VERSION 5.7 ;
  NAMESCASESENSITIVE ON ;
  NOWIREEXTENSIONATPIN ON ;
  DIVIDERCHAR "/" ;
  BUSBITCHARS "[]" ;
UNITS
  DATABASE MICRONS 200 ;
END UNITS

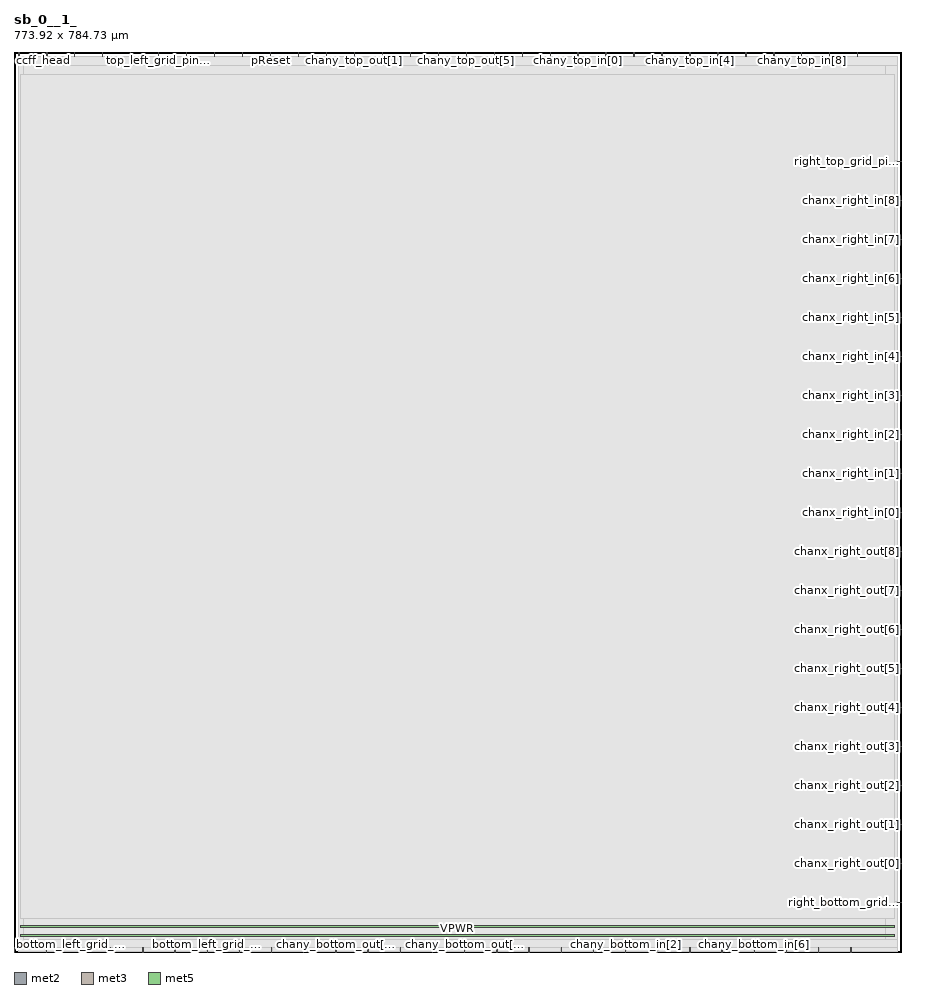
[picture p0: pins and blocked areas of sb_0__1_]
MACRO sb_0__1_
  CLASS BLOCK ;
  FOREIGN sb_0__1_ ;
  ORIGIN 0.000 0.000 ;
  SIZE 773.920 BY 784.730 ;
  PIN ccff_head
    DIRECTION INPUT ;
    PORT
      LAYER met2 ;
        RECT 4.140 780.730 4.420 784.730 ;
    END
  END ccff_head
  PIN top_left_grid_pin_1_
    DIRECTION INPUT ;
    PORT
      LAYER met2 ;
        RECT 28.520 780.730 28.800 784.730 ;
    END
  END top_left_grid_pin_1_
  PIN top_left_grid_pin_3_
    DIRECTION INPUT ;
    PORT
      LAYER met2 ;
        RECT 52.900 780.730 53.180 784.730 ;
    END
  END top_left_grid_pin_3_
  PIN top_left_grid_pin_5_
    DIRECTION INPUT ;
    PORT
      LAYER met2 ;
        RECT 77.280 780.730 77.560 784.730 ;
    END
  END top_left_grid_pin_5_
  PIN top_left_grid_pin_7_
    DIRECTION INPUT ;
    PORT
      LAYER met2 ;
        RECT 101.660 780.730 101.940 784.730 ;
    END
  END top_left_grid_pin_7_
  PIN top_left_grid_pin_9_
    DIRECTION INPUT ;
    PORT
      LAYER met2 ;
        RECT 126.040 780.730 126.320 784.730 ;
    END
  END top_left_grid_pin_9_
  PIN top_left_grid_pin_11_
    DIRECTION INPUT ;
    PORT
      LAYER met2 ;
        RECT 150.420 780.730 150.700 784.730 ;
    END
  END top_left_grid_pin_11_
  PIN top_left_grid_pin_13_
    DIRECTION INPUT ;
    PORT
      LAYER met2 ;
        RECT 174.800 780.730 175.080 784.730 ;
    END
  END top_left_grid_pin_13_
  PIN top_left_grid_pin_15_
    DIRECTION OUTPUT TRISTATE ;
    PORT
      LAYER met2 ;
        RECT 199.180 780.730 199.460 784.730 ;
    END
  END top_left_grid_pin_15_
  PIN pReset
    DIRECTION INPUT ;
    PORT
      LAYER met2 ;
        RECT 223.560 780.730 223.840 784.730 ;
    END
  END pReset
  PIN prog_clk
    DIRECTION INPUT ;
    PORT
      LAYER met2 ;
        RECT 247.940 780.730 248.220 784.730 ;
    END
  END prog_clk
  PIN chany_top_out[0]
    DIRECTION OUTPUT TRISTATE ;
    PORT
      LAYER met2 ;
        RECT 272.320 780.730 272.600 784.730 ;
    END
  END chany_top_out[0]
  PIN chany_top_out[1]
    DIRECTION OUTPUT TRISTATE ;
    PORT
      LAYER met2 ;
        RECT 296.700 780.730 296.980 784.730 ;
    END
  END chany_top_out[1]
  PIN chany_top_out[2]
    DIRECTION OUTPUT TRISTATE ;
    PORT
      LAYER met2 ;
        RECT 321.080 780.730 321.360 784.730 ;
    END
  END chany_top_out[2]
  PIN chany_top_out[3]
    DIRECTION OUTPUT TRISTATE ;
    PORT
      LAYER met2 ;
        RECT 345.460 780.730 345.740 784.730 ;
    END
  END chany_top_out[3]
  PIN chany_top_out[4]
    DIRECTION OUTPUT TRISTATE ;
    PORT
      LAYER met2 ;
        RECT 369.840 780.730 370.120 784.730 ;
    END
  END chany_top_out[4]
  PIN chany_top_out[5]
    DIRECTION OUTPUT TRISTATE ;
    PORT
      LAYER met2 ;
        RECT 394.220 780.730 394.500 784.730 ;
    END
  END chany_top_out[5]
  PIN chany_top_out[6]
    DIRECTION OUTPUT TRISTATE ;
    PORT
      LAYER met2 ;
        RECT 418.600 780.730 418.880 784.730 ;
    END
  END chany_top_out[6]
  PIN chany_top_out[7]
    DIRECTION OUTPUT TRISTATE ;
    PORT
      LAYER met2 ;
        RECT 442.980 780.730 443.260 784.730 ;
    END
  END chany_top_out[7]
  PIN chany_top_out[8]
    DIRECTION OUTPUT TRISTATE ;
    PORT
      LAYER met2 ;
        RECT 467.360 780.730 467.640 784.730 ;
    END
  END chany_top_out[8]
  PIN chany_top_in[0]
    DIRECTION INPUT ;
    PORT
      LAYER met2 ;
        RECT 491.740 780.730 492.020 784.730 ;
    END
  END chany_top_in[0]
  PIN chany_top_in[1]
    DIRECTION INPUT ;
    PORT
      LAYER met2 ;
        RECT 516.120 780.730 516.400 784.730 ;
    END
  END chany_top_in[1]
  PIN chany_top_in[2]
    DIRECTION INPUT ;
    PORT
      LAYER met2 ;
        RECT 540.500 780.730 540.780 784.730 ;
    END
  END chany_top_in[2]
  PIN chany_top_in[3]
    DIRECTION INPUT ;
    PORT
      LAYER met2 ;
        RECT 564.880 780.730 565.160 784.730 ;
    END
  END chany_top_in[3]
  PIN chany_top_in[4]
    DIRECTION INPUT ;
    PORT
      LAYER met2 ;
        RECT 589.260 780.730 589.540 784.730 ;
    END
  END chany_top_in[4]
  PIN chany_top_in[5]
    DIRECTION INPUT ;
    PORT
      LAYER met2 ;
        RECT 613.640 780.730 613.920 784.730 ;
    END
  END chany_top_in[5]
  PIN chany_top_in[6]
    DIRECTION INPUT ;
    PORT
      LAYER met2 ;
        RECT 638.020 780.730 638.300 784.730 ;
    END
  END chany_top_in[6]
  PIN chany_top_in[7]
    DIRECTION INPUT ;
    PORT
      LAYER met2 ;
        RECT 662.400 780.730 662.680 784.730 ;
    END
  END chany_top_in[7]
  PIN chany_top_in[8]
    DIRECTION INPUT ;
    PORT
      LAYER met2 ;
        RECT 686.780 780.730 687.060 784.730 ;
    END
  END chany_top_in[8]
  PIN ccff_tail
    DIRECTION OUTPUT TRISTATE ;
    PORT
      LAYER met2 ;
        RECT 711.160 780.730 711.440 784.730 ;
    END
  END ccff_tail
  PIN top_right_grid_pin_11_
    DIRECTION INPUT ;
    PORT
      LAYER met2 ;
        RECT 735.540 780.730 735.820 784.730 ;
    END
  END top_right_grid_pin_11_
  PIN right_bottom_grid_pin_12_
    DIRECTION INPUT ;
    PORT
      LAYER met3 ;
        RECT 769.920 42.880 773.920 43.480 ;
    END
  END right_bottom_grid_pin_12_
  PIN chanx_right_out[0]
    DIRECTION OUTPUT TRISTATE ;
    PORT
      LAYER met3 ;
        RECT 769.920 76.880 773.920 77.480 ;
    END
  END chanx_right_out[0]
  PIN chanx_right_out[1]
    DIRECTION OUTPUT TRISTATE ;
    PORT
      LAYER met3 ;
        RECT 769.920 110.880 773.920 111.480 ;
    END
  END chanx_right_out[1]
  PIN chanx_right_out[2]
    DIRECTION OUTPUT TRISTATE ;
    PORT
      LAYER met3 ;
        RECT 769.920 144.880 773.920 145.480 ;
    END
  END chanx_right_out[2]
  PIN chanx_right_out[3]
    DIRECTION OUTPUT TRISTATE ;
    PORT
      LAYER met3 ;
        RECT 769.920 178.880 773.920 179.480 ;
    END
  END chanx_right_out[3]
  PIN chanx_right_out[4]
    DIRECTION OUTPUT TRISTATE ;
    PORT
      LAYER met3 ;
        RECT 769.920 212.880 773.920 213.480 ;
    END
  END chanx_right_out[4]
  PIN chanx_right_out[5]
    DIRECTION OUTPUT TRISTATE ;
    PORT
      LAYER met3 ;
        RECT 769.920 246.880 773.920 247.480 ;
    END
  END chanx_right_out[5]
  PIN chanx_right_out[6]
    DIRECTION OUTPUT TRISTATE ;
    PORT
      LAYER met3 ;
        RECT 769.920 280.880 773.920 281.480 ;
    END
  END chanx_right_out[6]
  PIN chanx_right_out[7]
    DIRECTION OUTPUT TRISTATE ;
    PORT
      LAYER met3 ;
        RECT 769.920 314.880 773.920 315.480 ;
    END
  END chanx_right_out[7]
  PIN chanx_right_out[8]
    DIRECTION OUTPUT TRISTATE ;
    PORT
      LAYER met3 ;
        RECT 769.920 348.880 773.920 349.480 ;
    END
  END chanx_right_out[8]
  PIN chanx_right_in[0]
    DIRECTION INPUT ;
    PORT
      LAYER met3 ;
        RECT 769.920 382.880 773.920 383.480 ;
    END
  END chanx_right_in[0]
  PIN chanx_right_in[1]
    DIRECTION INPUT ;
    PORT
      LAYER met3 ;
        RECT 769.920 416.880 773.920 417.480 ;
    END
  END chanx_right_in[1]
  PIN chanx_right_in[2]
    DIRECTION INPUT ;
    PORT
      LAYER met3 ;
        RECT 769.920 450.880 773.920 451.480 ;
    END
  END chanx_right_in[2]
  PIN chanx_right_in[3]
    DIRECTION INPUT ;
    PORT
      LAYER met3 ;
        RECT 769.920 484.880 773.920 485.480 ;
    END
  END chanx_right_in[3]
  PIN chanx_right_in[4]
    DIRECTION INPUT ;
    PORT
      LAYER met3 ;
        RECT 769.920 518.880 773.920 519.480 ;
    END
  END chanx_right_in[4]
  PIN chanx_right_in[5]
    DIRECTION INPUT ;
    PORT
      LAYER met3 ;
        RECT 769.920 552.880 773.920 553.480 ;
    END
  END chanx_right_in[5]
  PIN chanx_right_in[6]
    DIRECTION INPUT ;
    PORT
      LAYER met3 ;
        RECT 769.920 586.880 773.920 587.480 ;
    END
  END chanx_right_in[6]
  PIN chanx_right_in[7]
    DIRECTION INPUT ;
    PORT
      LAYER met3 ;
        RECT 769.920 620.880 773.920 621.480 ;
    END
  END chanx_right_in[7]
  PIN chanx_right_in[8]
    DIRECTION INPUT ;
    PORT
      LAYER met3 ;
        RECT 769.920 654.880 773.920 655.480 ;
    END
  END chanx_right_in[8]
  PIN right_top_grid_pin_10_
    DIRECTION INPUT ;
    PORT
      LAYER met3 ;
        RECT 769.920 688.880 773.920 689.480 ;
    END
  END right_top_grid_pin_10_
  PIN bottom_left_grid_pin_1_
    DIRECTION INPUT ;
    PORT
      LAYER met2 ;
        RECT 0.000 0.000 0.280 4.000 ;
    END
  END bottom_left_grid_pin_1_
  PIN bottom_left_grid_pin_3_
    DIRECTION INPUT ;
    PORT
      LAYER met2 ;
        RECT 28.060 0.000 28.340 4.000 ;
    END
  END bottom_left_grid_pin_3_
  PIN bottom_left_grid_pin_5_
    DIRECTION INPUT ;
    PORT
      LAYER met2 ;
        RECT 56.120 0.000 56.400 4.000 ;
    END
  END bottom_left_grid_pin_5_
  PIN bottom_left_grid_pin_7_
    DIRECTION INPUT ;
    PORT
      LAYER met2 ;
        RECT 84.180 0.000 84.460 4.000 ;
    END
  END bottom_left_grid_pin_7_
  PIN bottom_left_grid_pin_9_
    DIRECTION INPUT ;
    PORT
      LAYER met2 ;
        RECT 112.240 0.000 112.520 4.000 ;
    END
  END bottom_left_grid_pin_9_
  PIN bottom_left_grid_pin_11_
    DIRECTION INPUT ;
    PORT
      LAYER met2 ;
        RECT 140.300 0.000 140.580 4.000 ;
    END
  END bottom_left_grid_pin_11_
  PIN bottom_left_grid_pin_13_
    DIRECTION INPUT ;
    PORT
      LAYER met2 ;
        RECT 168.360 0.000 168.640 4.000 ;
    END
  END bottom_left_grid_pin_13_
  PIN bottom_left_grid_pin_15_
    DIRECTION INPUT ;
    PORT
      LAYER met2 ;
        RECT 196.420 0.000 196.700 4.000 ;
    END
  END bottom_left_grid_pin_15_
  PIN chany_bottom_out[0]
    DIRECTION OUTPUT TRISTATE ;
    PORT
      LAYER met2 ;
        RECT 224.480 0.000 224.760 4.000 ;
    END
  END chany_bottom_out[0]
  PIN chany_bottom_out[1]
    DIRECTION OUTPUT TRISTATE ;
    PORT
      LAYER met2 ;
        RECT 252.540 0.000 252.820 4.000 ;
    END
  END chany_bottom_out[1]
  PIN chany_bottom_out[2]
    DIRECTION OUTPUT TRISTATE ;
    PORT
      LAYER met2 ;
        RECT 280.600 0.000 280.880 4.000 ;
    END
  END chany_bottom_out[2]
  PIN chany_bottom_out[3]
    DIRECTION OUTPUT TRISTATE ;
    PORT
      LAYER met2 ;
        RECT 308.660 0.000 308.940 4.000 ;
    END
  END chany_bottom_out[3]
  PIN chany_bottom_out[4]
    DIRECTION OUTPUT TRISTATE ;
    PORT
      LAYER met2 ;
        RECT 336.720 0.000 337.000 4.000 ;
    END
  END chany_bottom_out[4]
  PIN chany_bottom_out[5]
    DIRECTION OUTPUT TRISTATE ;
    PORT
      LAYER met2 ;
        RECT 364.780 0.000 365.060 4.000 ;
    END
  END chany_bottom_out[5]
  PIN chany_bottom_out[6]
    DIRECTION OUTPUT TRISTATE ;
    PORT
      LAYER met2 ;
        RECT 392.840 0.000 393.120 4.000 ;
    END
  END chany_bottom_out[6]
  PIN chany_bottom_out[7]
    DIRECTION OUTPUT TRISTATE ;
    PORT
      LAYER met2 ;
        RECT 420.900 0.000 421.180 4.000 ;
    END
  END chany_bottom_out[7]
  PIN chany_bottom_out[8]
    DIRECTION OUTPUT TRISTATE ;
    PORT
      LAYER met2 ;
        RECT 448.960 0.000 449.240 4.000 ;
    END
  END chany_bottom_out[8]
  PIN chany_bottom_in[0]
    DIRECTION INPUT ;
    PORT
      LAYER met2 ;
        RECT 477.020 0.000 477.300 4.000 ;
    END
  END chany_bottom_in[0]
  PIN chany_bottom_in[1]
    DIRECTION INPUT ;
    PORT
      LAYER met2 ;
        RECT 505.080 0.000 505.360 4.000 ;
    END
  END chany_bottom_in[1]
  PIN chany_bottom_in[2]
    DIRECTION INPUT ;
    PORT
      LAYER met2 ;
        RECT 533.140 0.000 533.420 4.000 ;
    END
  END chany_bottom_in[2]
  PIN chany_bottom_in[3]
    DIRECTION INPUT ;
    PORT
      LAYER met2 ;
        RECT 561.200 0.000 561.480 4.000 ;
    END
  END chany_bottom_in[3]
  PIN chany_bottom_in[4]
    DIRECTION INPUT ;
    PORT
      LAYER met2 ;
        RECT 589.260 0.000 589.540 4.000 ;
    END
  END chany_bottom_in[4]
  PIN chany_bottom_in[5]
    DIRECTION INPUT ;
    PORT
      LAYER met2 ;
        RECT 617.320 0.000 617.600 4.000 ;
    END
  END chany_bottom_in[5]
  PIN chany_bottom_in[6]
    DIRECTION INPUT ;
    PORT
      LAYER met2 ;
        RECT 645.380 0.000 645.660 4.000 ;
    END
  END chany_bottom_in[6]
  PIN chany_bottom_in[7]
    DIRECTION INPUT ;
    PORT
      LAYER met2 ;
        RECT 673.440 0.000 673.720 4.000 ;
    END
  END chany_bottom_in[7]
  PIN chany_bottom_in[8]
    DIRECTION INPUT ;
    PORT
      LAYER met2 ;
        RECT 701.500 0.000 701.780 4.000 ;
    END
  END chany_bottom_in[8]
  PIN bottom_right_grid_pin_11_
    DIRECTION INPUT ;
    PORT
      LAYER met2 ;
        RECT 729.560 0.000 729.840 4.000 ;
    END
  END bottom_right_grid_pin_11_
  PIN VPWR
    DIRECTION INPUT ;
    USE POWER ;
    PORT
      LAYER met5 ;
        RECT 5.430 13.840 768.110 15.440 ;
    END
  END VPWR
  PIN VGND
    DIRECTION INPUT ;
    USE GROUND ;
    PORT
      LAYER met5 ;
        RECT 5.430 21.340 768.110 22.940 ;
    END
  END VGND
  OBS
      LAYER li1 ;
        RECT 5.430 10.795 768.110 772.565 ;
      LAYER met1 ;
        RECT 3.660 0.040 770.340 772.720 ;
      LAYER met2 ;
        RECT 3.690 780.450 3.860 781.050 ;
        RECT 4.700 780.450 28.240 781.050 ;
        RECT 29.080 780.450 52.620 781.050 ;
        RECT 53.460 780.450 77.000 781.050 ;
        RECT 77.840 780.450 101.380 781.050 ;
        RECT 102.220 780.450 125.760 781.050 ;
        RECT 126.600 780.450 150.140 781.050 ;
        RECT 150.980 780.450 174.520 781.050 ;
        RECT 175.360 780.450 198.900 781.050 ;
        RECT 199.740 780.450 223.280 781.050 ;
        RECT 224.120 780.450 247.660 781.050 ;
        RECT 248.500 780.450 272.040 781.050 ;
        RECT 272.880 780.450 296.420 781.050 ;
        RECT 297.260 780.450 320.800 781.050 ;
        RECT 321.640 780.450 345.180 781.050 ;
        RECT 346.020 780.450 369.560 781.050 ;
        RECT 370.400 780.450 393.940 781.050 ;
        RECT 394.780 780.450 418.320 781.050 ;
        RECT 419.160 780.450 442.700 781.050 ;
        RECT 443.540 780.450 467.080 781.050 ;
        RECT 467.920 780.450 491.460 781.050 ;
        RECT 492.300 780.450 515.840 781.050 ;
        RECT 516.680 780.450 540.220 781.050 ;
        RECT 541.060 780.450 564.600 781.050 ;
        RECT 565.440 780.450 588.980 781.050 ;
        RECT 589.820 780.450 613.360 781.050 ;
        RECT 614.200 780.450 637.740 781.050 ;
        RECT 638.580 780.450 662.120 781.050 ;
        RECT 662.960 780.450 686.500 781.050 ;
        RECT 687.340 780.450 710.880 781.050 ;
        RECT 711.720 780.450 735.260 781.050 ;
        RECT 736.100 780.450 770.320 781.050 ;
        RECT 3.690 4.280 770.320 780.450 ;
        RECT 3.690 0.010 27.780 4.280 ;
        RECT 28.620 0.010 55.840 4.280 ;
        RECT 56.680 0.010 83.900 4.280 ;
        RECT 84.740 0.010 111.960 4.280 ;
        RECT 112.800 0.010 140.020 4.280 ;
        RECT 140.860 0.010 168.080 4.280 ;
        RECT 168.920 0.010 196.140 4.280 ;
        RECT 196.980 0.010 224.200 4.280 ;
        RECT 225.040 0.010 252.260 4.280 ;
        RECT 253.100 0.010 280.320 4.280 ;
        RECT 281.160 0.010 308.380 4.280 ;
        RECT 309.220 0.010 336.440 4.280 ;
        RECT 337.280 0.010 364.500 4.280 ;
        RECT 365.340 0.010 392.560 4.280 ;
        RECT 393.400 0.010 420.620 4.280 ;
        RECT 421.460 0.010 448.680 4.280 ;
        RECT 449.520 0.010 476.740 4.280 ;
        RECT 477.580 0.010 504.800 4.280 ;
        RECT 505.640 0.010 532.860 4.280 ;
        RECT 533.700 0.010 560.920 4.280 ;
        RECT 561.760 0.010 588.980 4.280 ;
        RECT 589.820 0.010 617.040 4.280 ;
        RECT 617.880 0.010 645.100 4.280 ;
        RECT 645.940 0.010 673.160 4.280 ;
        RECT 674.000 0.010 701.220 4.280 ;
        RECT 702.060 0.010 729.280 4.280 ;
        RECT 730.120 0.010 770.320 4.280 ;
      LAYER met3 ;
        RECT 8.630 689.880 770.560 772.645 ;
        RECT 8.630 688.480 769.520 689.880 ;
        RECT 8.630 655.880 770.560 688.480 ;
        RECT 8.630 654.480 769.520 655.880 ;
        RECT 8.630 621.880 770.560 654.480 ;
        RECT 8.630 620.480 769.520 621.880 ;
        RECT 8.630 587.880 770.560 620.480 ;
        RECT 8.630 586.480 769.520 587.880 ;
        RECT 8.630 553.880 770.560 586.480 ;
        RECT 8.630 552.480 769.520 553.880 ;
        RECT 8.630 519.880 770.560 552.480 ;
        RECT 8.630 518.480 769.520 519.880 ;
        RECT 8.630 485.880 770.560 518.480 ;
        RECT 8.630 484.480 769.520 485.880 ;
        RECT 8.630 451.880 770.560 484.480 ;
        RECT 8.630 450.480 769.520 451.880 ;
        RECT 8.630 417.880 770.560 450.480 ;
        RECT 8.630 416.480 769.520 417.880 ;
        RECT 8.630 383.880 770.560 416.480 ;
        RECT 8.630 382.480 769.520 383.880 ;
        RECT 8.630 349.880 770.560 382.480 ;
        RECT 8.630 348.480 769.520 349.880 ;
        RECT 8.630 315.880 770.560 348.480 ;
        RECT 8.630 314.480 769.520 315.880 ;
        RECT 8.630 281.880 770.560 314.480 ;
        RECT 8.630 280.480 769.520 281.880 ;
        RECT 8.630 247.880 770.560 280.480 ;
        RECT 8.630 246.480 769.520 247.880 ;
        RECT 8.630 213.880 770.560 246.480 ;
        RECT 8.630 212.480 769.520 213.880 ;
        RECT 8.630 179.880 770.560 212.480 ;
        RECT 8.630 178.480 769.520 179.880 ;
        RECT 8.630 145.880 770.560 178.480 ;
        RECT 8.630 144.480 769.520 145.880 ;
        RECT 8.630 111.880 770.560 144.480 ;
        RECT 8.630 110.480 769.520 111.880 ;
        RECT 8.630 77.880 770.560 110.480 ;
        RECT 8.630 76.480 769.520 77.880 ;
        RECT 8.630 43.880 770.560 76.480 ;
        RECT 8.630 42.480 769.520 43.880 ;
        RECT 8.630 10.715 770.560 42.480 ;
      LAYER met4 ;
        RECT 8.630 10.640 760.230 772.720 ;
      LAYER met5 ;
        RECT 5.430 28.840 768.110 765.440 ;
  END
END sb_0__1_
END LIBRARY

